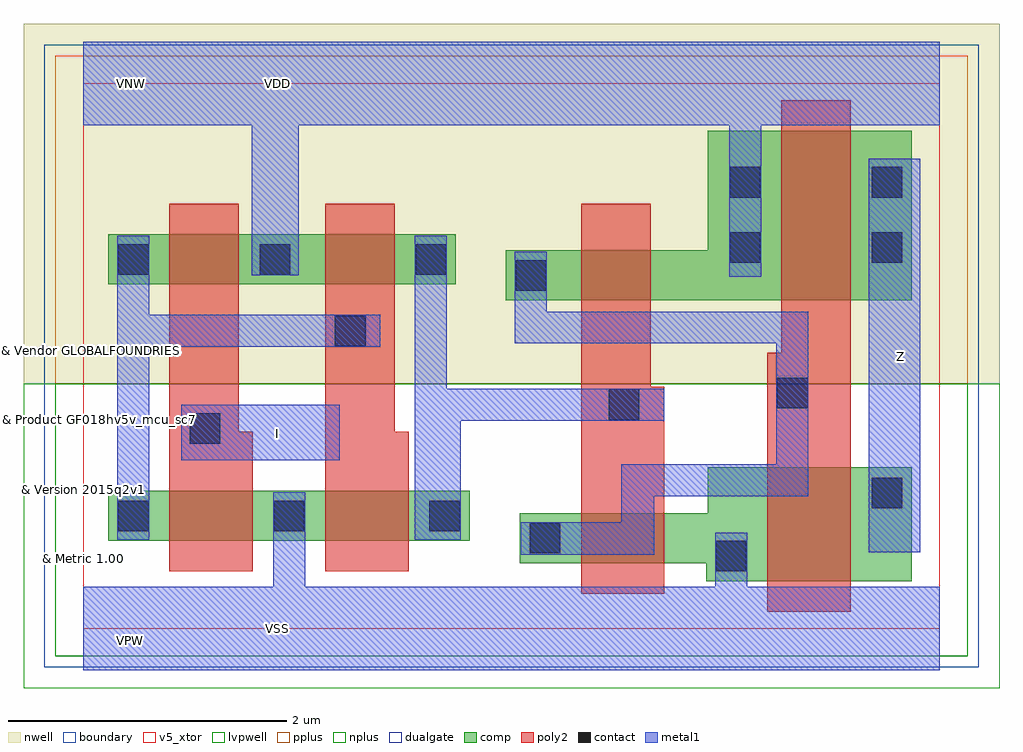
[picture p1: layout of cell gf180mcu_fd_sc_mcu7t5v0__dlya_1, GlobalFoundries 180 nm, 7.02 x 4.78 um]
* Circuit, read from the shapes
.subckt gf180mcu_fd_sc_mcu7t5v0__dlya_1 I VDD VNW VSS Z
XM1 VSS I n1 VSUBS nfet_05v0 w=0.36u l=0.6u
XM2 n2 n1 VSS VSUBS nfet_05v0 w=0.36u l=0.6u
XM3 VSS n2 n3 VSUBS nfet_05v0 w=0.36u l=0.6u
XM4 Z n3 VSS VSUBS nfet_05v0 w=0.82u l=0.6u
XM5 VDD I n1 VNW pfet_05v0 w=0.36u l=0.5u
XM6 n2 n1 VDD VNW pfet_05v0 w=0.36u l=0.5u
XM7 VDD n2 n3 VNW pfet_05v0 w=0.36u l=0.5u
XM8 Z n3 VDD VNW pfet_05v0 w=1.22u l=0.5u
.ends

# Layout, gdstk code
import gdstk
lib = gdstk.Library(unit=1e-6, precision=1e-09)
def R(c, l, rs):  # rectangles x0, y0, x1, y1
    for r in rs: c.add(gdstk.rectangle(r[:2], r[2:], *l))
def A(c, l, x, y, w, h, nx, ny, dx, dy):  # array of equal rectangles
    R(c, l, [(x+i*dx, y+j*dy, x+i*dx+w, y+j*dy+h) for i in range(nx) for j in range(ny)])
def P(c, l, *ps):  # polygons
    for p in ps: c.add(gdstk.Polygon(p, *l))
boundary = (0, 0)
nwell = (21, 0)
comp = (22, 0)
poly2 = (30, 0)
pplus = (31, 0)
nplus = (32, 0)
contact = (33, 0)
metal1 = (34, 0)
dualgate = (55, 0)
v5_xtor = (112, 1)
lvpwell = (204, 0)

gf180mcu_fd_sc_mcu7t5v0_ = lib.new_cell('gf180mcu_fd_sc_mcu7t5v0__dlya_1')
R(gf180mcu_fd_sc_mcu7t5v0_, boundary, [(0,0,6.16,3.92)])
R(gf180mcu_fd_sc_mcu7t5v0_, nwell, [(-0.43,1.76,6.59,4.35)])
R(gf180mcu_fd_sc_mcu7t5v0_, comp, [(0.18,0.63,2.78,0.99), (0.18,2.475,2.68,2.835)])
P(gf180mcu_fd_sc_mcu7t5v0_, comp, [(4.48,0.34),(4.48,0.47),(3.14,0.47),(3.14,0.83),(4.49,0.83),(4.49,1.16),(5.96,1.16),(5.96,0.34)],
  [(3.04,2.36),(3.04,2.72),(4.49,2.72),(4.49,3.58),(5.96,3.58),(5.96,2.36)])
P(gf180mcu_fd_sc_mcu7t5v0_, poly2, [(0.62,0.41),(0.62,3.055),(1.12,3.055),(1.12,1.415),(1.22,1.415),(1.22,0.41)],
  [(1.74,0.41),(1.74,3.055),(2.24,3.055),(2.24,1.415),(2.34,1.415),(2.34,0.41)],
  [(3.58,0.25),(3.58,3.055),(4.08,3.055),(4.08,1.74),(4.18,1.74),(4.18,0.25)],
  [(4.92,0.12),(4.92,1.985),(5.02,1.985),(5.02,3.8),(5.52,3.8),(5.52,0.12)])
R(gf180mcu_fd_sc_mcu7t5v0_, pplus, [(-0.2,1.76,6.36,4.12)])
R(gf180mcu_fd_sc_mcu7t5v0_, nplus, [(-0.2,-0.2,6.36,1.76)])
A(gf180mcu_fd_sc_mcu7t5v0_, contact, 0.25, 0.7, 0.22, 0.22, 3, 1, 1.12, 0)
R(gf180mcu_fd_sc_mcu7t5v0_, contact, [(4.55,0.41,4.77,0.63), (3.21,0.54,3.43,0.76), (5.67,0.865,5.89,1.085), (0.765,1.33,0.985,1.55), (3.78,1.5,4,1.72), (4.99,1.585,5.21,1.805), (1.81,2.03,2.03,2.25), (3.11,2.43,3.33,2.65), (0.25,2.545,0.47,2.765), (1.27,2.545,1.49,2.765), (2.39,2.545,2.61,2.765), (4.65,2.63,4.87,2.85), (5.67,2.63,5.89,2.85), (4.65,3.1,4.87,3.32), (5.67,3.1,5.89,3.32)])
R(gf180mcu_fd_sc_mcu7t5v0_, metal1, [(5.65,0.55,6.02,3.38), (0.705,1.21,1.845,1.61)])
P(gf180mcu_fd_sc_mcu7t5v0_, metal1, [(0.245,0.64),(0.245,2.825),(0.475,2.825),(0.475,2.255),(2.135,2.255),(2.135,2.025),(0.475,2.025),(0.475,0.64)],
  [(2.385,0.64),(2.385,2.825),(2.615,2.825),(2.615,1.725),(4.18,1.725),(4.18,1.495),(2.715,1.495),(2.715,0.64)],
  [(3.145,0.53),(3.145,0.765),(3.87,0.765),(3.87,1.18),(4.985,1.18),(4.985,2.05),(3.105,2.05),(3.105,2.71),(3.335,2.71),(3.335,2.28),(5.215,2.28),(5.215,0.95),(4.105,0.95),(4.105,0.53)],
  [(0,-0.3),(0,0.3),(1.365,0.3),(1.365,0.98),(1.595,0.98),(1.595,0.3),(4.545,0.3),(4.545,0.69),(4.775,0.69),(4.775,0.3),(6.16,0.3),(6.16,-0.3)],
  [(4.645,2.53),(4.645,3.62),(1.55,3.62),(1.55,2.54),(1.21,2.54),(1.21,3.62),(0,3.62),(0,4.22),(6.16,4.22),(6.16,3.62),(4.875,3.62),(4.875,2.53)])
R(gf180mcu_fd_sc_mcu7t5v0_, dualgate, [(-0.28,-0.28,6.44,4.2)])
R(gf180mcu_fd_sc_mcu7t5v0_, v5_xtor, [(0,0,6.16,3.92)])
R(gf180mcu_fd_sc_mcu7t5v0_, lvpwell, [(-0.43,-0.43,6.59,1.76)])
gf180mcu_fd_sc_mcu7t5v0_.add(gdstk.Label('VSS', (1.4,0), layer=34, texttype=10))
gf180mcu_fd_sc_mcu7t5v0_.add(gdstk.Label('Z', (5.88,1.96), layer=34, texttype=10))
gf180mcu_fd_sc_mcu7t5v0_.add(gdstk.Label('I', (1.4,1.4), layer=34, texttype=10))
gf180mcu_fd_sc_mcu7t5v0_.add(gdstk.Label('VDD', (1.4,3.92), layer=34, texttype=10))
gf180mcu_fd_sc_mcu7t5v0_.add(gdstk.Label('& Vendor GLOBALFOUNDRIES', (0,2), layer=63, texttype=63))
gf180mcu_fd_sc_mcu7t5v0_.add(gdstk.Label('& Product GF018hv5v_mcu_sc7', (0,1.5), layer=63, texttype=63))
gf180mcu_fd_sc_mcu7t5v0_.add(gdstk.Label('& Version 2015q2v1', (0,1), layer=63, texttype=63))
gf180mcu_fd_sc_mcu7t5v0_.add(gdstk.Label('& Metric 1.00', (0,0.5), layer=63, texttype=63))
gf180mcu_fd_sc_mcu7t5v0_.add(gdstk.Label('VNW', (0.345,3.92), layer=21, texttype=10))
gf180mcu_fd_sc_mcu7t5v0_.add(gdstk.Label('VPW', (0.34,-0.085), layer=204, texttype=10))

lib.write_gds('gf180mcu_fd_sc_mcu7t5v0__dlya_1.gds')
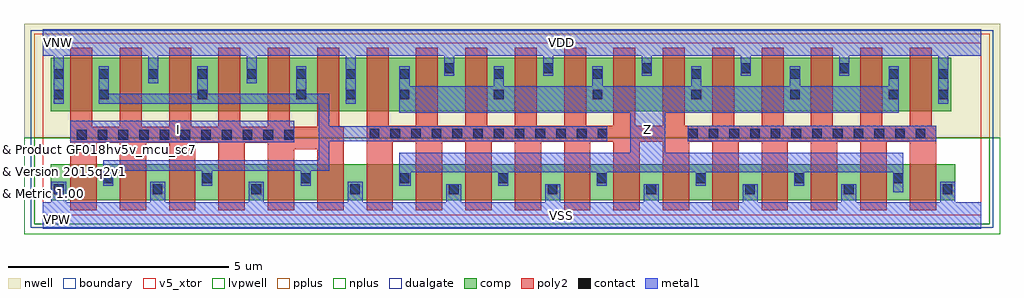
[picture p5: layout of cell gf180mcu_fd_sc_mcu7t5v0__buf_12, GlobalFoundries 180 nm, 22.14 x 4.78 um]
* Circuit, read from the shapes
.subckt gf180mcu_fd_sc_mcu7t5v0__buf_12 I VDD VNW VSS Z
XM1 n1 I VSS VSUBS nfet_05v0 w=0.82u l=0.6u m=6
XM2 Z n1 VSS VSUBS nfet_05v0 w=0.82u l=0.6u m=12
XM3 n1 I VDD VNW pfet_05v0 w=1.22u l=0.5u m=6
XM4 Z n1 VDD VNW pfet_05v0 w=1.22u l=0.5u m=12
.ends

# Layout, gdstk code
import gdstk
lib = gdstk.Library(unit=1e-6, precision=1e-09)
def R(c, l, rs):  # rectangles x0, y0, x1, y1
    for r in rs: c.add(gdstk.rectangle(r[:2], r[2:], *l))
def A(c, l, x, y, w, h, nx, ny, dx, dy):  # array of equal rectangles
    R(c, l, [(x+i*dx, y+j*dy, x+i*dx+w, y+j*dy+h) for i in range(nx) for j in range(ny)])
def P(c, l, *ps):  # polygons
    for p in ps: c.add(gdstk.Polygon(p, *l))
boundary = (0, 0)
nwell = (21, 0)
comp = (22, 0)
poly2 = (30, 0)
pplus = (31, 0)
nplus = (32, 0)
contact = (33, 0)
metal1 = (34, 0)
dualgate = (55, 0)
v5_xtor = (112, 1)
lvpwell = (204, 0)

gf180mcu_fd_sc_mcu7t5v0_ = lib.new_cell('gf180mcu_fd_sc_mcu7t5v0__buf_12')
R(gf180mcu_fd_sc_mcu7t5v0_, boundary, [(0,0,21.28,3.92)])
R(gf180mcu_fd_sc_mcu7t5v0_, nwell, [(-0.43,1.76,21.71,4.35)])
R(gf180mcu_fd_sc_mcu7t5v0_, comp, [(0.18,0.34,20.7,1.16), (0.18,2.36,20.6,3.58)])
P(gf180mcu_fd_sc_mcu7t5v0_, poly2, [(0.62,0.12),(0.62,3.8),(1.12,3.8),(1.12,2.01),(1.74,2.01),(1.74,3.8),(2.24,3.8),(2.24,2.01),(2.86,2.01),(2.86,3.8),(3.36,3.8),(3.36,2.01),(3.98,2.01),(3.98,3.8),(4.48,3.8),(4.48,2.01),(5.1,2.01),(5.1,3.8),(5.6,3.8),(5.6,2.01),(6.22,2.01),(6.22,3.8),(6.72,3.8),(6.72,2.01),(6.82,2.01),(6.82,0.12),(6.22,0.12),(6.22,1.5),(5.7,1.5),(5.7,0.12),(5.1,0.12),(5.1,1.65),(4.58,1.65),(4.58,0.12),(3.98,0.12),(3.98,1.65),(3.46,1.65),(3.46,0.12),(2.86,0.12),(2.86,1.65),(2.34,1.65),(2.34,0.12),(1.74,0.12),(1.74,1.65),(1.22,1.65),(1.22,0.12)],
  [(7.34,0.12),(7.34,3.8),(7.84,3.8),(7.84,2.035),(8.46,2.035),(8.46,3.8),(8.96,3.8),(8.96,2.035),(9.58,2.035),(9.58,3.8),(10.08,3.8),(10.08,2.035),(10.7,2.035),(10.7,3.8),(11.2,3.8),(11.2,2.035),(11.82,2.035),(11.82,3.8),(12.32,3.8),(12.32,2.035),(12.94,2.035),(12.94,3.8),(13.44,3.8),(13.44,2.035),(14.06,2.035),(14.06,3.8),(14.56,3.8),(14.56,2.035),(15.18,2.035),(15.18,3.8),(15.68,3.8),(15.68,2.035),(16.3,2.035),(16.3,3.8),(16.8,3.8),(16.8,2.035),(17.42,2.035),(17.42,3.8),(17.92,3.8),(17.92,2.035),(18.54,2.035),(18.54,3.8),(19.04,3.8),(19.04,2.035),(19.66,2.035),(19.66,3.8),(20.16,3.8),(20.16,2.035),(20.26,2.035),(20.26,0.12),(19.66,0.12),(19.66,1.675),(19.14,1.675),(19.14,0.12),(18.54,0.12),(18.54,1.675),(18.02,1.675),(18.02,0.12),(17.42,0.12),(17.42,1.675),(16.9,1.675),(16.9,0.12),(16.3,0.12),(16.3,1.675),(15.78,1.675),(15.78,0.12),(15.18,0.12),(15.18,1.675),(14.66,1.675),(14.66,0.12),(14.06,0.12),(14.06,1.675),(13.54,1.675),(13.54,0.12),(12.94,0.12),(12.94,1.675),(12.42,1.675),(12.42,0.12),(11.82,0.12),(11.82,1.675),(11.3,1.675),(11.3,0.12),(10.7,0.12),(10.7,1.675),(10.18,1.675),(10.18,0.12),(9.58,0.12),(9.58,1.675),(9.06,1.675),(9.06,0.12),(8.46,0.12),(8.46,1.675),(7.94,1.675),(7.94,0.12)])
R(gf180mcu_fd_sc_mcu7t5v0_, pplus, [(-0.2,1.76,21.48,4.12)])
R(gf180mcu_fd_sc_mcu7t5v0_, nplus, [(-0.2,-0.2,21.48,1.76)])
A(gf180mcu_fd_sc_mcu7t5v0_, contact, 0.25, 0.485, 0.22, 0.22, 10, 1, 2.24, 0)
A(gf180mcu_fd_sc_mcu7t5v0_, contact, 1.37, 0.735, 0.22, 0.22, 9, 1, 2.24, 0)
A(gf180mcu_fd_sc_mcu7t5v0_, contact, 0.77, 1.72, 0.22, 0.22, 11, 1, 0.47, 0)
A(gf180mcu_fd_sc_mcu7t5v0_, contact, 7.41, 1.745, 0.22, 0.22, 12, 1, 0.47, 0)
A(gf180mcu_fd_sc_mcu7t5v0_, contact, 14.63, 1.745, 0.22, 0.22, 12, 1, 0.47, 0)
A(gf180mcu_fd_sc_mcu7t5v0_, contact, 1.27, 2.63, 0.22, 0.22, 3, 1, 2.24, 0)
A(gf180mcu_fd_sc_mcu7t5v0_, contact, 10.23, 2.63, 0.22, 0.22, 5, 2, 2.24, 0.47)
A(gf180mcu_fd_sc_mcu7t5v0_, contact, 1.27, 3.1, 0.22, 0.22, 6, 1, 1.12, 0)
A(gf180mcu_fd_sc_mcu7t5v0_, contact, 9.11, 3.23, 0.22, 0.22, 5, 1, 2.24, 0)
R(gf180mcu_fd_sc_mcu7t5v0_, contact, [(0.25,2.63,0.47,2.85), (6.87,2.63,7.09,2.85), (8.09,2.63,8.31,2.85), (20.31,2.63,20.53,2.85), (0.25,3.1,0.47,3.32), (8.09,3.1,8.31,3.32), (20.31,3.1,20.53,3.32)])
R(gf180mcu_fd_sc_mcu7t5v0_, metal1, [(0.62,1.66,5.7,2.15), (14.625,1.685,20.26,2.03)])
P(gf180mcu_fd_sc_mcu7t5v0_, metal1, [(1.365,0.675),(1.365,1.25),(6.26,1.25),(6.26,2.53),(1.265,2.53),(1.265,3.38),(1.495,3.38),(1.495,2.76),(3.505,2.76),(3.505,3.38),(3.735,3.38),(3.735,2.76),(5.745,2.76),(5.745,3.38),(5.975,3.38),(5.975,2.76),(6.495,2.76),(6.495,2.025),(12.805,2.025),(12.805,1.685),(6.495,1.685),(6.495,1.015),(6.075,1.015),(6.075,0.675),(5.845,0.675),(5.845,1.015),(3.835,1.015),(3.835,0.675),(3.605,0.675),(3.605,1.015),(1.595,1.015),(1.595,0.675)],
  [(19.285,0.53),(19.285,0.98),(17.275,0.98),(17.275,0.675),(17.045,0.675),(17.045,0.98),(15.035,0.98),(15.035,0.675),(14.805,0.675),(14.805,0.98),(12.795,0.98),(12.795,0.675),(12.565,0.675),(12.565,0.98),(10.555,0.98),(10.555,0.675),(10.325,0.675),(10.325,0.98),(8.345,0.98),(8.345,0.675),(8.085,0.675),(8.085,1.42),(13.32,1.42),(13.32,2.33),(8.085,2.33),(8.085,3.38),(8.315,3.38),(8.315,2.93),(10.225,2.93),(10.225,3.38),(10.455,3.38),(10.455,2.93),(12.465,2.93),(12.465,3.38),(12.695,3.38),(12.695,2.93),(14.705,2.93),(14.705,3.38),(14.935,3.38),(14.935,2.93),(16.945,2.93),(16.945,3.38),(17.175,3.38),(17.175,2.93),(19.185,2.93),(19.185,3.38),(19.415,3.38),(19.415,2.33),(14.12,2.33),(14.12,1.42),(19.515,1.42),(19.515,0.53)],
  [(0,-0.3),(0,0.3),(0.19,0.3),(0.19,0.765),(0.53,0.765),(0.53,0.3),(2.43,0.3),(2.43,0.765),(2.77,0.765),(2.77,0.3),(4.67,0.3),(4.67,0.765),(5.01,0.765),(5.01,0.3),(6.91,0.3),(6.91,0.765),(7.25,0.765),(7.25,0.3),(9.15,0.3),(9.15,0.71),(9.49,0.71),(9.49,0.3),(11.39,0.3),(11.39,0.71),(11.73,0.71),(11.73,0.3),(13.63,0.3),(13.63,0.71),(13.97,0.71),(13.97,0.3),(15.87,0.3),(15.87,0.71),(16.21,0.71),(16.21,0.3),(18.11,0.3),(18.11,0.71),(18.45,0.71),(18.45,0.3),(20.35,0.3),(20.35,0.765),(20.69,0.765),(20.69,0.3),(21.28,0.3),(21.28,-0.3)],
  [(0.245,2.53),(0.245,3.62),(0,3.62),(0,4.22),(21.28,4.22),(21.28,3.62),(20.535,3.62),(20.535,2.53),(20.305,2.53),(20.305,3.62),(18.295,3.62),(18.295,3.17),(18.065,3.17),(18.065,3.62),(16.055,3.62),(16.055,3.17),(15.825,3.17),(15.825,3.62),(13.815,3.62),(13.815,3.17),(13.585,3.17),(13.585,3.62),(11.575,3.62),(11.575,3.17),(11.345,3.17),(11.345,3.62),(9.335,3.62),(9.335,3.17),(9.105,3.17),(9.105,3.62),(7.095,3.62),(7.095,2.53),(6.865,2.53),(6.865,3.62),(4.855,3.62),(4.855,3),(4.625,3),(4.625,3.62),(2.615,3.62),(2.615,3),(2.385,3),(2.385,3.62),(0.475,3.62),(0.475,2.53)])
R(gf180mcu_fd_sc_mcu7t5v0_, dualgate, [(-0.28,-0.28,21.56,4.2)])
R(gf180mcu_fd_sc_mcu7t5v0_, v5_xtor, [(0,0,21.28,3.92)])
R(gf180mcu_fd_sc_mcu7t5v0_, lvpwell, [(-0.43,-0.43,21.71,1.76)])
gf180mcu_fd_sc_mcu7t5v0_.add(gdstk.Label('Z', (13.72,1.96), layer=34, texttype=10))
gf180mcu_fd_sc_mcu7t5v0_.add(gdstk.Label('I', (3.08,1.96), layer=34, texttype=10))
gf180mcu_fd_sc_mcu7t5v0_.add(gdstk.Label('VDD', (11.76,3.92), layer=34, texttype=10))
gf180mcu_fd_sc_mcu7t5v0_.add(gdstk.Label('VSS', (11.76,0), layer=34, texttype=10))
gf180mcu_fd_sc_mcu7t5v0_.add(gdstk.Label('& Vendor GLOBALFOUNDRIES', (0,2), layer=63, texttype=63))
gf180mcu_fd_sc_mcu7t5v0_.add(gdstk.Label('& Product GF018hv5v_mcu_sc7', (0,1.5), layer=63, texttype=63))
gf180mcu_fd_sc_mcu7t5v0_.add(gdstk.Label('& Version 2015q2v1', (0,1), layer=63, texttype=63))
gf180mcu_fd_sc_mcu7t5v0_.add(gdstk.Label('& Metric 1.00', (0,0.5), layer=63, texttype=63))
gf180mcu_fd_sc_mcu7t5v0_.add(gdstk.Label('VNW', (0.345,3.92), layer=21, texttype=10))
gf180mcu_fd_sc_mcu7t5v0_.add(gdstk.Label('VPW', (0.34,-0.085), layer=204, texttype=10))

lib.write_gds('gf180mcu_fd_sc_mcu7t5v0__buf_12.gds')
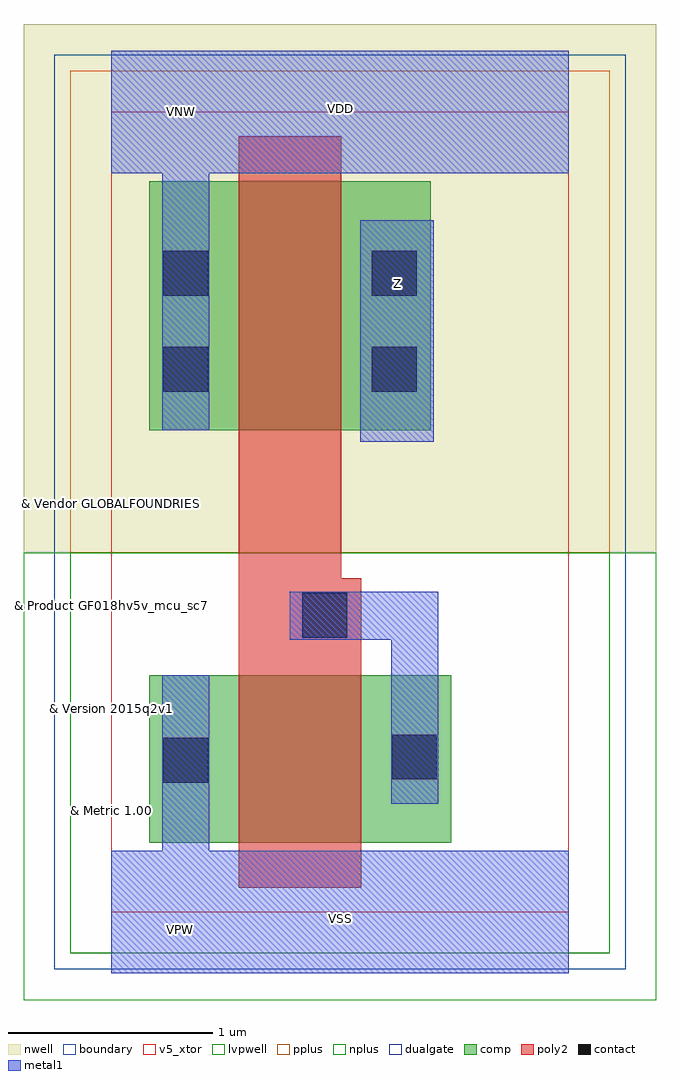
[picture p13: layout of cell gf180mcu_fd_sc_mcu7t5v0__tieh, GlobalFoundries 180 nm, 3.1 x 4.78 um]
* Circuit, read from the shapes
.subckt gf180mcu_fd_sc_mcu7t5v0__tieh VDD VNW VSS Z
XM1 n1 n1 VSS VSUBS nfet_05v0 w=0.82u l=0.6u
XM2 Z n1 VDD VNW pfet_05v0 w=1.22u l=0.5u
.ends

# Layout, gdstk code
import gdstk
lib = gdstk.Library(unit=1e-6, precision=1e-09)
def R(c, l, rs):  # rectangles x0, y0, x1, y1
    for r in rs: c.add(gdstk.rectangle(r[:2], r[2:], *l))
def P(c, l, *ps):  # polygons
    for p in ps: c.add(gdstk.Polygon(p, *l))
boundary = (0, 0)
nwell = (21, 0)
comp = (22, 0)
poly2 = (30, 0)
pplus = (31, 0)
nplus = (32, 0)
contact = (33, 0)
metal1 = (34, 0)
dualgate = (55, 0)
v5_xtor = (112, 1)
lvpwell = (204, 0)

gf180mcu_fd_sc_mcu7t5v0_ = lib.new_cell('gf180mcu_fd_sc_mcu7t5v0__tieh')
R(gf180mcu_fd_sc_mcu7t5v0_, boundary, [(0,0,2.24,3.92)])
R(gf180mcu_fd_sc_mcu7t5v0_, nwell, [(-0.43,1.76,2.67,4.35)])
R(gf180mcu_fd_sc_mcu7t5v0_, comp, [(0.185,0.34,1.665,1.16), (0.185,2.36,1.565,3.58)])
P(gf180mcu_fd_sc_mcu7t5v0_, poly2, [(0.625,0.12),(0.625,3.8),(1.125,3.8),(1.125,1.635),(1.225,1.635),(1.225,0.12)])
R(gf180mcu_fd_sc_mcu7t5v0_, pplus, [(-0.2,1.76,2.44,4.12)])
R(gf180mcu_fd_sc_mcu7t5v0_, nplus, [(-0.2,-0.2,2.44,1.76)])
R(gf180mcu_fd_sc_mcu7t5v0_, contact, [(0.255,0.635,0.475,0.855), (1.375,0.65,1.595,0.87), (0.935,1.345,1.155,1.565), (0.255,2.55,0.475,2.77), (1.275,2.55,1.495,2.77), (0.255,3.02,0.475,3.24), (1.275,3.02,1.495,3.24)])
R(gf180mcu_fd_sc_mcu7t5v0_, metal1, [(1.22,2.305,1.58,3.39)])
P(gf180mcu_fd_sc_mcu7t5v0_, metal1, [(1.37,0.53),(1.37,1.335),(0.875,1.335),(0.875,1.57),(1.6,1.57),(1.6,0.53)],
  [(0,-0.3),(0,0.3),(0.25,0.3),(0.25,1.16),(0.48,1.16),(0.48,0.3),(2.24,0.3),(2.24,-0.3)],
  [(0.25,2.36),(0.25,3.62),(0,3.62),(0,4.22),(2.24,4.22),(2.24,3.62),(0.48,3.62),(0.48,2.36)])
R(gf180mcu_fd_sc_mcu7t5v0_, dualgate, [(-0.28,-0.28,2.52,4.2)])
R(gf180mcu_fd_sc_mcu7t5v0_, v5_xtor, [(0,0,2.24,3.92)])
R(gf180mcu_fd_sc_mcu7t5v0_, lvpwell, [(-0.43,-0.43,2.67,1.76)])
gf180mcu_fd_sc_mcu7t5v0_.add(gdstk.Label('Z', (1.4,3.08), layer=34, texttype=10))
gf180mcu_fd_sc_mcu7t5v0_.add(gdstk.Label('VDD', (1.12,3.935), layer=34, texttype=10))
gf180mcu_fd_sc_mcu7t5v0_.add(gdstk.Label('VSS', (1.12,-0.03), layer=34, texttype=10))
gf180mcu_fd_sc_mcu7t5v0_.add(gdstk.Label('& Vendor GLOBALFOUNDRIES', (0,2), layer=63, texttype=63))
gf180mcu_fd_sc_mcu7t5v0_.add(gdstk.Label('& Product GF018hv5v_mcu_sc7', (0,1.5), layer=63, texttype=63))
gf180mcu_fd_sc_mcu7t5v0_.add(gdstk.Label('& Version 2015q2v1', (0,1), layer=63, texttype=63))
gf180mcu_fd_sc_mcu7t5v0_.add(gdstk.Label('& Metric 1.00', (0,0.5), layer=63, texttype=63))
gf180mcu_fd_sc_mcu7t5v0_.add(gdstk.Label('VNW', (0.345,3.92), layer=21, texttype=10))
gf180mcu_fd_sc_mcu7t5v0_.add(gdstk.Label('VPW', (0.34,-0.085), layer=204, texttype=10))

lib.write_gds('gf180mcu_fd_sc_mcu7t5v0__tieh.gds')
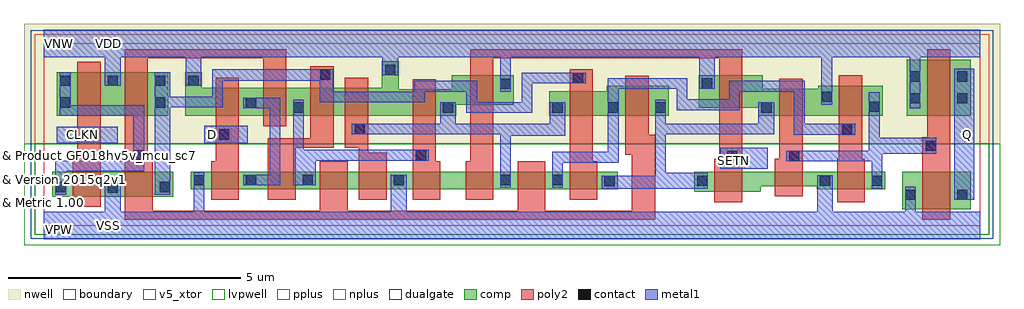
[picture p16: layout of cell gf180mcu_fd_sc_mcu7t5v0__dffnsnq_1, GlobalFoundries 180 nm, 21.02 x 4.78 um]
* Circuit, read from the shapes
.subckt gf180mcu_fd_sc_mcu7t5v0__dffnsnq_1 CLKN D Q SETN VDD VNW VSS
XM1 VSS CLKN n1 VSUBS nfet_05v0 w=0.54u l=0.6u
XM2 n2 n1 VSS VSUBS nfet_05v0 w=0.54u l=0.6u
XM3 n3 D VSS VSUBS nfet_05v0 w=0.38u l=0.6u
XM4 n4 n2 n3 VSUBS nfet_05v0 w=0.38u l=0.6u
XM5 n5 n1 n4 VSUBS nfet_05v0 w=0.38u l=0.6u
XM6 VSS n6 n5 VSUBS nfet_05v0 w=0.38u l=0.6u
XM7 n7 n4 VSS VSUBS nfet_05v0 w=0.38u l=0.6u
XM8 n6 SETN n7 VSUBS nfet_05v0 w=0.38u l=0.6u
XM9 n8 n1 n6 VSUBS nfet_05v0 w=0.38u l=0.6u
XM10 n9 n2 n8 VSUBS nfet_05v0 w=0.38u l=0.6u
XM11 n10 SETN n9 VSUBS nfet_05v0 w=0.435u l=0.6u
XM12 VSS n11 n10 VSUBS nfet_05v0 w=0.31u l=0.6u
XM13 n11 n8 VSS VSUBS nfet_05v0 w=0.375u l=0.6u
XM14 Q n11 VSS VSUBS nfet_05v0 w=0.815u l=0.6u
XM15 VDD CLKN n1 VNW pfet_05v0 w=0.94u l=0.5u
XM16 n2 n1 VDD VNW pfet_05v0 w=0.94u l=0.5u
XM17 n3 D VDD VNW pfet_05v0 w=0.605u l=0.5u
XM18 n4 n1 n3 VNW pfet_05v0 w=0.605u l=0.5u
XM19 n12 n2 n4 VNW pfet_05v0 w=0.605u l=0.5u
XM20 VDD n6 n12 VNW pfet_05v0 w=0.605u l=0.5u
XM21 n6 n4 VDD VNW pfet_05v0 w=0.57u l=0.5u
XM22 VDD SETN n6 VNW pfet_05v0 w=0.63u l=0.5u
XM23 n8 n2 n6 VNW pfet_05v0 w=0.535u l=0.5u
XM24 n9 n1 n8 VNW pfet_05v0 w=0.65u l=0.5u
XM25 n9 SETN VDD VNW pfet_05v0 w=0.705u l=0.5u
XM26 VDD n11 n9 VNW pfet_05v0 w=0.58u l=0.5u
XM27 n11 n8 VDD VNW pfet_05v0 w=0.655u l=0.5u
XM28 Q n11 VDD VNW pfet_05v0 w=1.215u l=0.5u
.ends

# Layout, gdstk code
import gdstk
lib = gdstk.Library(unit=1e-6, precision=1e-09)
def R(c, l, rs):  # rectangles x0, y0, x1, y1
    for r in rs: c.add(gdstk.rectangle(r[:2], r[2:], *l))
def A(c, l, x, y, w, h, nx, ny, dx, dy):  # array of equal rectangles
    R(c, l, [(x+i*dx, y+j*dy, x+i*dx+w, y+j*dy+h) for i in range(nx) for j in range(ny)])
def P(c, l, *ps):  # polygons
    for p in ps: c.add(gdstk.Polygon(p, *l))
boundary = (0, 0)
nwell = (21, 0)
comp = (22, 0)
poly2 = (30, 0)
pplus = (31, 0)
nplus = (32, 0)
contact = (33, 0)
metal1 = (34, 0)
dualgate = (55, 0)
v5_xtor = (112, 1)
lvpwell = (204, 0)

gf180mcu_fd_sc_mcu7t5v0_ = lib.new_cell('gf180mcu_fd_sc_mcu7t5v0__dffnsnq_1')
R(gf180mcu_fd_sc_mcu7t5v0_, boundary, [(0,0,20.16,3.92)])
R(gf180mcu_fd_sc_mcu7t5v0_, nwell, [(-0.43,1.76,20.59,4.35)])
R(gf180mcu_fd_sc_mcu7t5v0_, comp, [(18.48,0.345,19.96,1.16), (0.18,0.62,2.78,1.16), (3.16,0.78,12.36,1.16), (0.28,2.36,2.68,3.3), (18.58,2.36,19.96,3.575)])
P(gf180mcu_fd_sc_mcu7t5v0_, comp, [(3.04,2.36),(3.04,3.3),(3.4,3.3),(3.4,2.965),(7.28,2.965),(7.28,3.535),(7.64,3.535),(7.64,2.93),(8.78,2.93),(8.78,3.235),(10.12,3.235),(10.12,2.605),(8.88,2.605),(8.88,2.36)],
  [(10.88,2.36),(10.88,2.895),(12.12,2.895),(12.12,3.01),(13.46,3.01),(13.46,2.36)],
  [(15.38,2.36),(15.38,2.535),(14.1,2.535),(14.1,3.24),(15.48,3.24),(15.48,2.94),(16.68,2.94),(16.68,3.015),(18.06,3.015),(18.06,2.36)],
  [(14,0.725),(14,1.16),(18.12,1.16),(18.12,0.785),(16.64,0.785),(16.64,0.85),(15.44,0.85),(15.44,0.725)])
P(gf180mcu_fd_sc_mcu7t5v0_, poly2, [(0.62,0.4),(0.62,1.44),(0.72,1.44),(0.72,3.525),(1.22,3.525),(1.22,0.4)],
  [(3.6,0.56),(3.6,1.38),(3.7,1.38),(3.7,3.185),(4.2,3.185),(4.2,0.56)],
  [(4.82,0.56),(4.82,1.88),(5.74,1.88),(5.74,3.425),(6.24,3.425),(6.24,1.68),(5.42,1.68),(5.42,0.56)],
  [(6.78,0.56),(6.78,1.68),(6.48,1.68),(6.48,3.185),(6.98,3.185),(6.98,1.57),(7.38,1.57),(7.38,0.56)],
  [(7.94,0.56),(7.94,3.15),(8.44,3.15),(8.44,1.38),(8.54,1.38),(8.54,0.56)],
  [(11.32,0.56),(11.32,3.36),(11.82,3.36),(11.82,1.38),(11.92,1.38),(11.92,0.56)],
  [(1.74,0.12),(1.74,3.8),(5.22,3.8),(5.22,2.14),(4.72,2.14),(4.72,3.6),(2.24,3.6),(2.24,1.44),(2.34,1.44),(2.34,0.32),(5.94,0.32),(5.94,1.38),(6.54,1.38),(6.54,0.32),(10.2,0.32),(10.2,1.38),(10.8,1.38),(10.8,0.32),(12.66,0.32),(12.66,1.52),(12.52,1.52),(12.52,3.23),(13.02,3.23),(13.02,1.96),(13.16,1.96),(13.16,0.12)],
  [(14.44,0.505),(14.44,1.44),(14.54,1.44),(14.54,3.6),(9.68,3.6),(9.68,0.56),(9.08,0.56),(9.08,1.38),(9.18,1.38),(9.18,3.8),(15.04,3.8),(15.04,0.505)],
  [(15.74,0.63),(15.74,1.44),(15.84,1.44),(15.84,3.16),(16.34,3.16),(16.34,0.63)],
  [(17.08,0.505),(17.08,1.44),(17.12,1.44),(17.12,3.24),(17.62,3.24),(17.62,1.44),(17.68,1.44),(17.68,0.505)],
  [(18.92,0.12),(18.92,1.9),(19.02,1.9),(19.02,3.8),(19.52,3.8),(19.52,0.12)])
R(gf180mcu_fd_sc_mcu7t5v0_, pplus, [(-0.2,1.76,20.36,4.12)])
R(gf180mcu_fd_sc_mcu7t5v0_, nplus, [(-0.2,-0.2,20.36,1.76)])
A(gf180mcu_fd_sc_mcu7t5v0_, contact, 0.35, 3.01, 0.22, 0.22, 3, 1, 1.02, 0)
R(gf180mcu_fd_sc_mcu7t5v0_, contact, [(18.55,0.555,18.77,0.775), (19.67,0.555,19.89,0.775), (1.37,0.71,1.59,0.93), (0.25,0.72,0.47,0.94), (2.49,0.72,2.71,0.94), (12.07,0.85,12.29,1.07), (14.07,0.855,14.29,1.075), (16.71,0.855,16.93,1.075), (17.83,0.855,18.05,1.075), (3.23,0.865,3.45,1.085), (7.53,0.865,7.75,1.085), (4.35,0.87,4.57,1.09), (5.57,0.87,5.79,1.09), (9.83,0.87,10.05,1.09), (10.95,0.87,11.17,1.09), (14.715,1.39,14.935,1.61), (16.05,1.39,16.27,1.61), (1.93,1.405,2.15,1.625), (8.01,1.405,8.23,1.625), (18.99,1.61,19.21,1.83), (0.79,1.825,1.01,2.045), (3.77,1.85,3.99,2.07), (6.69,1.97,6.91,2.19), (17.19,1.97,17.41,2.19), (5.37,2.43,5.59,2.65), (8.59,2.43,8.81,2.65), (10.95,2.43,11.17,2.65), (12.15,2.43,12.37,2.65), (13.17,2.43,13.39,2.65), (15.45,2.43,15.67,2.65), (17.77,2.45,17.99,2.67), (4.35,2.525,4.57,2.745), (0.35,2.54,0.57,2.76), (2.39,2.54,2.61,2.76), (18.65,2.63,18.87,2.85), (19.67,2.63,19.89,2.85), (16.75,2.66,16.97,2.88), (9.83,2.945,10.05,3.165), (14.17,2.95,14.39,3.17), (3.11,3.01,3.33,3.23), (11.39,3.07,11.61,3.29), (18.65,3.1,18.87,3.32), (19.67,3.1,19.89,3.32), (5.95,3.135,6.17,3.355), (7.35,3.245,7.57,3.465)])
R(gf180mcu_fd_sc_mcu7t5v0_, metal1, [(19.61,0.55,20.04,3.38), (14.56,1.22,15.59,1.67), (0.28,1.77,1.59,2.13), (3.45,1.77,4.39,2.15)])
P(gf180mcu_fd_sc_mcu7t5v0_, metal1, [(0.245,0.66),(0.245,1.395),(1.925,1.395),(1.925,2.36),(0.345,2.36),(0.345,3.3),(0.575,3.3),(0.575,2.595),(2.155,2.595),(2.155,1.165),(0.475,1.165),(0.475,0.66)],
  [(4.29,0.865),(4.29,1.095),(4.86,1.095),(4.86,2.52),(4.29,2.52),(4.29,2.75),(5.09,2.75),(5.09,0.865)],
  [(5.365,0.865),(5.365,2.71),(5.595,2.71),(5.595,1.63),(8.29,1.63),(8.29,1.395),(5.85,1.395),(5.85,0.865)],
  [(9.825,0.81),(9.825,1.965),(6.63,1.965),(6.63,2.195),(8.53,2.195),(8.53,2.655),(8.87,2.655),(8.87,2.195),(10.89,2.195),(10.89,2.655),(11.23,2.655),(11.23,1.93),(10.055,1.93),(10.055,0.81)],
  [(2.385,0.66),(2.385,3.3),(2.715,3.3),(2.715,2.775),(3.62,2.775),(3.62,3.36),(6.23,3.36),(6.23,2.88),(7.975,2.88),(7.975,3.115),(9.33,3.115),(9.33,2.655),(10.285,2.655),(10.285,3.295),(11.67,3.295),(11.67,3.065),(10.515,3.065),(10.515,2.425),(9.1,2.425),(9.1,2.885),(8.205,2.885),(8.205,2.65),(5.94,2.65),(5.94,3.12),(3.85,3.12),(3.85,2.545),(2.715,2.545),(2.715,0.66)],
  [(12.01,0.795),(12.01,1.075),(13.165,1.075),(13.165,2.71),(13.395,2.71),(13.395,2.195),(15.38,2.195),(15.38,2.655),(15.73,2.655),(15.73,1.965),(13.395,1.965),(13.395,1.135),(14.295,1.135),(14.295,0.795)],
  [(10.945,0.81),(10.945,1.585),(12.145,1.585),(12.145,3.175),(13.855,3.175),(13.855,2.715),(14.755,2.715),(14.755,3.12),(16.38,3.12),(16.38,2.195),(17.47,2.195),(17.47,1.96),(16.15,1.96),(16.15,2.885),(14.985,2.885),(14.985,2.48),(13.625,2.48),(13.625,2.94),(12.375,2.94),(12.375,1.355),(11.175,1.355),(11.175,0.81)],
  [(17.825,0.795),(17.825,1.385),(15.99,1.385),(15.99,1.615),(17.765,1.615),(17.765,2.875),(17.995,2.875),(17.995,1.895),(19.215,1.895),(19.215,1.545),(18.055,1.545),(18.055,0.795)],
  [(0,-0.3),(0,0.3),(1.31,0.3),(1.31,0.935),(1.65,0.935),(1.65,0.3),(3.225,0.3),(3.225,1.145),(3.455,1.145),(3.455,0.3),(7.47,0.3),(7.47,1.09),(7.81,1.09),(7.81,0.3),(16.65,0.3),(16.65,1.08),(16.99,1.08),(16.99,0.3),(18.545,0.3),(18.545,0.835),(18.775,0.835),(18.775,0.3),(20.16,0.3),(20.16,-0.3)],
  [(18.645,2.53),(18.645,3.62),(16.975,3.62),(16.975,2.6),(16.745,2.6),(16.745,3.62),(14.45,3.62),(14.45,2.945),(14.11,2.945),(14.11,3.62),(10.055,3.62),(10.055,2.885),(9.825,2.885),(9.825,3.62),(7.63,3.62),(7.63,3.24),(7.29,3.24),(7.29,3.62),(3.39,3.62),(3.39,3.005),(3.05,3.005),(3.05,3.62),(1.65,3.62),(1.65,3.005),(1.31,3.005),(1.31,3.62),(0,3.62),(0,4.22),(20.16,4.22),(20.16,3.62),(18.875,3.62),(18.875,2.53)])
R(gf180mcu_fd_sc_mcu7t5v0_, dualgate, [(-0.28,-0.28,20.44,4.2)])
R(gf180mcu_fd_sc_mcu7t5v0_, v5_xtor, [(0,0,20.16,3.92)])
R(gf180mcu_fd_sc_mcu7t5v0_, lvpwell, [(-0.43,-0.43,20.59,1.76)])
gf180mcu_fd_sc_mcu7t5v0_.add(gdstk.Label('CLKN', (0.84,1.96), layer=34, texttype=10))
gf180mcu_fd_sc_mcu7t5v0_.add(gdstk.Label('Q', (19.88,1.96), layer=34, texttype=10))
gf180mcu_fd_sc_mcu7t5v0_.add(gdstk.Label('SETN', (14.84,1.4), layer=34, texttype=10))
gf180mcu_fd_sc_mcu7t5v0_.add(gdstk.Label('VDD', (1.4,3.92), layer=34, texttype=10))
gf180mcu_fd_sc_mcu7t5v0_.add(gdstk.Label('VSS', (1.4,0), layer=34, texttype=10))
gf180mcu_fd_sc_mcu7t5v0_.add(gdstk.Label('D', (3.64,1.96), layer=34, texttype=10))
gf180mcu_fd_sc_mcu7t5v0_.add(gdstk.Label('& Vendor GLOBALFOUNDRIES', (0,2), layer=63, texttype=63))
gf180mcu_fd_sc_mcu7t5v0_.add(gdstk.Label('& Product GF018hv5v_mcu_sc7', (0,1.5), layer=63, texttype=63))
gf180mcu_fd_sc_mcu7t5v0_.add(gdstk.Label('& Version 2015q2v1', (0,1), layer=63, texttype=63))
gf180mcu_fd_sc_mcu7t5v0_.add(gdstk.Label('& Metric 1.00', (0,0.5), layer=63, texttype=63))
gf180mcu_fd_sc_mcu7t5v0_.add(gdstk.Label('VNW', (0.345,3.92), layer=21, texttype=10))
gf180mcu_fd_sc_mcu7t5v0_.add(gdstk.Label('VPW', (0.34,-0.085), layer=204, texttype=10))

lib.write_gds('gf180mcu_fd_sc_mcu7t5v0__dffnsnq_1.gds')
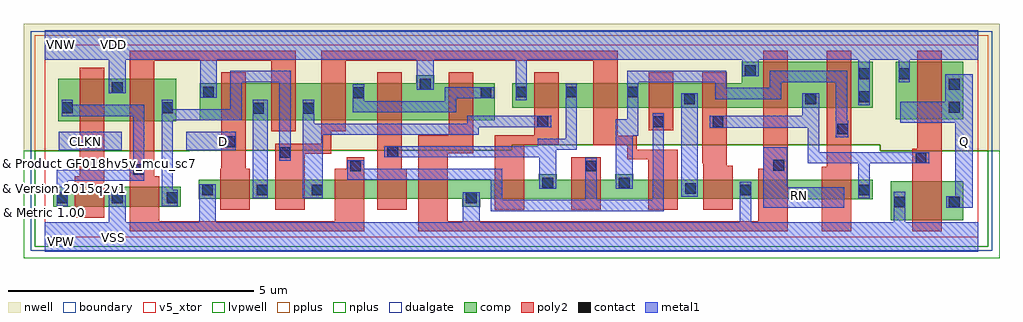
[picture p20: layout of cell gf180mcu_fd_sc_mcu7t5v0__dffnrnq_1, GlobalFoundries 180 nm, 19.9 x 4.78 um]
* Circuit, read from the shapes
.subckt gf180mcu_fd_sc_mcu7t5v0__dffnrnq_1 CLKN D Q RN VDD VNW VSS
XM1 VSS CLKN n1 VSUBS nfet_05v0 w=0.405u l=0.6u
XM2 n2 n1 VSS VSUBS nfet_05v0 w=0.405u l=0.6u
XM3 n3 D VSS VSUBS nfet_05v0 w=0.39u l=0.6u
XM4 n4 n2 n3 VSUBS nfet_05v0 w=0.39u l=0.6u
XM5 n5 n1 n4 VSUBS nfet_05v0 w=0.39u l=0.6u
XM6 n6 n7 n5 VSUBS nfet_05v0 w=0.39u l=0.6u
XM7 VSS RN n6 VSUBS nfet_05v0 w=0.39u l=0.6u
XM8 n7 n4 VSS VSUBS nfet_05v0 w=0.39u l=0.6u
XM9 n8 n1 n7 VSUBS nfet_05v0 w=0.39u l=0.6u
XM10 n9 n2 n8 VSUBS nfet_05v0 w=0.39u l=0.6u
XM11 VSS n10 n9 VSUBS nfet_05v0 w=0.39u l=0.6u
XM12 n11 RN VSS VSUBS nfet_05v0 w=0.39u l=0.6u
XM13 n10 n8 n11 VSUBS nfet_05v0 w=0.4u l=0.6u
XM14 Q n10 VSS VSUBS nfet_05v0 w=0.795u l=0.6u
XM15 VDD CLKN n1 VNW pfet_05v0 w=0.865u l=0.5u
XM16 n2 n1 VDD VNW pfet_05v0 w=0.865u l=0.5u
XM17 n3 D VDD VNW pfet_05v0 w=0.76u l=0.5u
XM18 n4 n1 n3 VNW pfet_05v0 w=0.76u l=0.5u
XM19 n12 n2 n4 VNW pfet_05v0 w=0.76u l=0.5u
XM20 VDD n7 n12 VNW pfet_05v0 w=0.76u l=0.5u
XM21 n12 RN VDD VNW pfet_05v0 w=0.76u l=0.5u
XM22 n7 n4 VDD VNW pfet_05v0 w=0.505u l=0.5u
XM23 n8 n2 n7 VNW pfet_05v0 w=0.505u l=0.5u
XM24 n9 n1 n8 VNW pfet_05v0 w=0.505u l=0.5u
XM25 VDD n10 n9 VNW pfet_05v0 w=0.505u l=0.5u
XM26 n10 RN VDD VNW pfet_05v0 w=0.94u l=0.5u
XM27 VDD n8 n10 VNW pfet_05v0 w=0.94u l=0.5u
XM28 Q n10 VDD VNW pfet_05v0 w=1.175u l=0.5u
.ends

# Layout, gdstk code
import gdstk
lib = gdstk.Library(unit=1e-6, precision=1e-09)
def R(c, l, rs):  # rectangles x0, y0, x1, y1
    for r in rs: c.add(gdstk.rectangle(r[:2], r[2:], *l))
def A(c, l, x, y, w, h, nx, ny, dx, dy):  # array of equal rectangles
    R(c, l, [(x+i*dx, y+j*dy, x+i*dx+w, y+j*dy+h) for i in range(nx) for j in range(ny)])
def P(c, l, *ps):  # polygons
    for p in ps: c.add(gdstk.Polygon(p, *l))
boundary = (0, 0)
nwell = (21, 0)
comp = (22, 0)
poly2 = (30, 0)
pplus = (31, 0)
nplus = (32, 0)
contact = (33, 0)
metal1 = (34, 0)
dualgate = (55, 0)
v5_xtor = (112, 1)
lvpwell = (204, 0)

gf180mcu_fd_sc_mcu7t5v0_ = lib.new_cell('gf180mcu_fd_sc_mcu7t5v0__dffnrnq_1')
R(gf180mcu_fd_sc_mcu7t5v0_, boundary, [(0,0,19.04,3.92)])
P(gf180mcu_fd_sc_mcu7t5v0_, nwell, [(-0.43,1.76),(-0.43,4.35),(19.47,4.35),(19.47,1.76),(17.04,1.76),(17.04,1.885),(9.525,1.885),(9.525,1.77),(2.96,1.77),(2.96,1.76)])
R(gf180mcu_fd_sc_mcu7t5v0_, comp, [(17.25,0.345,18.73,1.14), (0.18,0.62,2.78,1.025), (0.28,2.36,2.68,3.225), (17.35,2.405,18.73,3.58)])
P(gf180mcu_fd_sc_mcu7t5v0_, comp, [(3.16,2.38),(3.16,3.14),(7.58,3.14),(7.58,3.3),(7.94,3.3),(7.94,3.14),(9.18,3.14),(9.18,2.38)],
  [(8.52,0.62),(8.52,0.78),(3.14,0.78),(3.14,1.17),(10.08,1.17),(10.08,1.285),(10.44,1.285),(10.44,1.17),(11.64,1.17),(11.64,1.285),(12,1.285),(12,1.17),(16.89,1.17),(16.89,0.77),(15.45,0.77),(15.45,0.78),(8.88,0.78),(8.88,0.62)],
  [(9.54,2.635),(9.54,3.14),(14.21,3.14),(14.21,3.575),(16.89,3.575),(16.89,2.635)])
R(gf180mcu_fd_sc_mcu7t5v0_, poly2, [(10.74,0.56,11.34,1.63), (12.315,2.175,12.815,3.36)])
P(gf180mcu_fd_sc_mcu7t5v0_, poly2, [(0.62,0.4),(0.62,1.245),(0.72,1.245),(0.72,3.45),(1.22,3.45),(1.22,0.4)],
  [(3.58,0.56),(3.58,1.39),(3.6,1.39),(3.6,3.36),(4.1,3.36),(4.1,1.39),(4.18,1.39),(4.18,0.56)],
  [(1.74,0.12),(1.74,3.8),(5.12,3.8),(5.12,2.16),(4.62,2.16),(4.62,3.6),(2.24,3.6),(2.24,1.245),(2.34,1.245),(2.34,0.32),(5.92,0.32),(5.92,1.39),(6.16,1.39),(6.16,1.63),(6.52,1.63),(6.52,0.12)],
  [(6.78,0.56),(6.78,3.36),(7.28,3.36),(7.28,1.39),(7.38,1.39),(7.38,0.56)],
  [(9.18,0.56),(9.18,2.08),(9.98,2.08),(9.98,3.36),(10.48,3.36),(10.48,1.88),(9.78,1.88),(9.78,0.56)],
  [(4.7,0.56),(4.7,1.905),(5.64,1.905),(5.64,3.8),(11.69,3.8),(11.69,2.07),(12.075,2.07),(12.075,1.785),(12.91,1.785),(12.91,0.56),(12.31,0.56),(12.31,1.585),(11.875,1.585),(11.875,1.87),(11.19,1.87),(11.19,3.6),(6.14,3.6),(6.14,2.16),(5.84,2.16),(5.84,1.705),(5.3,1.705),(5.3,0.56)],
  [(13.43,0.56),(13.43,1.505),(13.41,1.505),(13.41,3.36),(13.91,3.36),(13.91,1.455),(14.03,1.455),(14.03,0.56)],
  [(7.62,0.12),(7.62,2.08),(8.24,2.08),(8.24,3.36),(8.74,3.36),(8.74,1.715),(8.22,1.715),(8.22,0.32),(14.55,0.32),(14.55,1.39),(14.65,1.39),(14.65,3.8),(15.15,3.8),(15.15,0.12)],
  [(15.85,0.12),(15.85,1.44),(15.95,1.44),(15.95,3.8),(16.45,3.8),(16.45,0.12)],
  [(17.69,0.12),(17.69,1.8),(17.79,1.8),(17.79,3.8),(18.29,3.8),(18.29,0.12)])
P(gf180mcu_fd_sc_mcu7t5v0_, pplus, [(-0.2,1.76),(-0.2,4.12),(19.24,4.12),(19.24,1.76),(17.04,1.76),(17.04,1.885),(9.525,1.885),(9.525,1.77),(2.96,1.77),(2.96,1.76)])
P(gf180mcu_fd_sc_mcu7t5v0_, nplus, [(-0.2,-0.2),(-0.2,1.76),(2.96,1.76),(2.96,1.77),(9.525,1.77),(9.525,1.885),(17.04,1.885),(17.04,1.76),(19.24,1.76),(19.24,-0.2)])
A(gf180mcu_fd_sc_mcu7t5v0_, contact, 0.25, 0.69, 0.22, 0.22, 3, 1, 1.12, 0)
A(gf180mcu_fd_sc_mcu7t5v0_, contact, 3.21, 0.85, 0.22, 0.22, 3, 1, 1.12, 0)
R(gf180mcu_fd_sc_mcu7t5v0_, contact, [(17.32,0.605,17.54,0.825), (18.44,0.605,18.66,0.825), (8.59,0.69,8.81,0.91), (14.18,0.85,14.4,1.07), (16.6,0.85,16.82,1.07), (13.06,0.88,13.28,1.1), (10.15,0.995,10.37,1.215), (11.71,0.995,11.93,1.215), (1.81,1.27,2.03,1.49), (6.23,1.34,6.45,1.56), (11.03,1.34,11.25,1.56), (14.86,1.355,15.08,1.575), (17.76,1.51,17.98,1.73), (4.79,1.615,5.01,1.835), (6.99,1.63,7.21,1.85), (0.79,1.82,1.01,2.04), (3.67,1.835,3.89,2.055), (16.16,2.095,16.38,2.315), (10.05,2.245,10.27,2.465), (12.4,2.245,12.62,2.465), (13.62,2.245,13.84,2.465), (4.25,2.52,4.47,2.74), (5.27,2.52,5.49,2.74), (0.35,2.525,0.57,2.745), (2.39,2.525,2.61,2.745), (18.44,2.54,18.66,2.76), (13.04,2.705,13.26,2.925), (15.51,2.705,15.73,2.925), (16.6,2.75,16.82,2.97), (6.29,2.835,6.51,3.055), (8.89,2.835,9.11,3.055), (3.23,2.85,3.45,3.07), (9.61,2.85,9.83,3.07), (10.63,2.85,10.85,3.07), (11.88,2.85,12.1,3.07), (1.37,2.935,1.59,3.155), (7.65,3.01,7.87,3.23), (18.44,3.01,18.66,3.23), (16.6,3.22,16.82,3.44), (17.42,3.22,17.64,3.44), (14.28,3.285,14.5,3.505)])
R(gf180mcu_fd_sc_mcu7t5v0_, metal1, [(4.245,0.79,4.555,2.8), (12.98,0.82,13.32,2.93), (0.29,1.77,1.575,2.15), (2.89,1.77,3.895,2.15)])
P(gf180mcu_fd_sc_mcu7t5v0_, metal1, [(0.245,0.63),(0.245,1.375),(1.805,1.375),(1.805,2.465),(0.345,2.465),(0.345,2.805),(0.575,2.805),(0.575,2.7),(2.035,2.7),(2.035,1.145),(0.475,1.145),(0.475,0.63)],
  [(2.385,0.63),(2.385,2.805),(2.615,2.805),(2.615,2.61),(3.785,2.61),(3.785,3.39),(5.015,3.39),(5.015,1.555),(4.785,1.555),(4.785,3.16),(4.015,3.16),(4.015,2.38),(2.615,2.38),(2.615,0.97),(2.715,0.97),(2.715,0.63)],
  [(6.285,2.545),(6.285,3.115),(6.515,3.115),(6.515,2.775),(8.16,2.775),(8.16,3.06),(9.17,3.06),(9.17,2.83),(8.39,2.83),(8.39,2.545)],
  [(5.265,0.79),(5.265,2.8),(5.495,2.8),(5.495,2.315),(8.62,2.315),(8.62,2.47),(10.33,2.47),(10.33,2.24),(8.85,2.24),(8.85,2.085),(5.675,2.085),(5.675,0.79)],
  [(10.09,0.99),(10.09,1.625),(6.93,1.625),(6.93,1.855),(10.06,1.855),(10.06,2.01),(10.625,2.01),(10.625,3.13),(10.855,3.13),(10.855,1.78),(10.43,1.78),(10.43,0.99)],
  [(9.1,0.53),(9.1,1.165),(6.17,1.165),(6.17,1.565),(6.515,1.565),(6.515,1.395),(9.33,1.395),(9.33,0.76),(11.025,0.76),(11.025,1.62),(11.255,1.62),(11.255,0.76),(12.395,0.76),(12.395,2.525),(12.625,2.525),(12.625,0.53)],
  [(14.65,0.6),(14.65,1.83),(15.14,1.83),(15.14,1.02),(16.3,1.02),(16.3,0.6)],
  [(11.645,0.99),(11.645,2.405),(11.875,2.405),(11.875,3.39),(13.9,3.39),(13.9,3.05),(14.79,3.05),(14.79,3.39),(16.365,3.39),(16.365,2.375),(16.385,2.375),(16.385,2.035),(16.135,2.035),(16.135,3.16),(15.02,3.16),(15.02,2.815),(13.67,2.815),(13.67,3.16),(12.105,3.16),(12.105,2.065),(11.995,2.065),(11.995,0.99)],
  [(16.595,0.79),(16.595,1.505),(15.56,1.505),(15.56,2.235),(13.56,2.235),(13.56,2.47),(15.45,2.47),(15.45,2.93),(15.79,2.93),(15.79,1.735),(18.04,1.735),(18.04,1.505),(16.825,1.505),(16.825,0.79)],
  [(18.38,0.6),(18.38,0.83),(18.57,0.83),(18.57,2.33),(17.45,2.33),(17.45,2.765),(18.365,2.765),(18.365,3.32),(18.92,3.32),(18.92,0.6)],
  [(0,-0.3),(0,0.3),(1.31,0.3),(1.31,0.915),(1.65,0.915),(1.65,0.3),(3.15,0.3),(3.15,1.075),(3.49,1.075),(3.49,0.3),(8.53,0.3),(8.53,0.915),(8.87,0.915),(8.87,0.3),(14.175,0.3),(14.175,1.13),(14.405,1.13),(14.405,0.3),(17.315,0.3),(17.315,0.93),(17.545,0.93),(17.545,0.3),(19.04,0.3),(19.04,-0.3)],
  [(16.595,2.69),(16.595,3.62),(14.56,3.62),(14.56,3.28),(14.22,3.28),(14.22,3.62),(9.835,3.62),(9.835,2.79),(9.605,2.79),(9.605,3.62),(7.93,3.62),(7.93,3.005),(7.59,3.005),(7.59,3.62),(3.51,3.62),(3.51,2.845),(3.17,2.845),(3.17,3.62),(1.65,3.62),(1.65,2.93),(1.31,2.93),(1.31,3.62),(0,3.62),(0,4.22),(19.04,4.22),(19.04,3.62),(17.645,3.62),(17.645,3.16),(17.415,3.16),(17.415,3.62),(16.825,3.62),(16.825,2.69)])
R(gf180mcu_fd_sc_mcu7t5v0_, dualgate, [(-0.28,-0.28,19.32,4.2)])
R(gf180mcu_fd_sc_mcu7t5v0_, v5_xtor, [(0,0,19.04,3.92)])
P(gf180mcu_fd_sc_mcu7t5v0_, lvpwell, [(-0.43,-0.43),(-0.43,1.76),(2.96,1.76),(2.96,1.77),(9.525,1.77),(9.525,1.885),(17.04,1.885),(17.04,1.76),(19.47,1.76),(19.47,-0.43)])
gf180mcu_fd_sc_mcu7t5v0_.add(gdstk.Label('D', (3.64,1.96), layer=34, texttype=10))
gf180mcu_fd_sc_mcu7t5v0_.add(gdstk.Label('VSS', (1.4,0), layer=34, texttype=10))
gf180mcu_fd_sc_mcu7t5v0_.add(gdstk.Label('CLKN', (0.84,1.96), layer=34, texttype=10))
gf180mcu_fd_sc_mcu7t5v0_.add(gdstk.Label('RN', (15.4,0.84), layer=34, texttype=10))
gf180mcu_fd_sc_mcu7t5v0_.add(gdstk.Label('Q', (18.76,1.96), layer=34, texttype=10))
gf180mcu_fd_sc_mcu7t5v0_.add(gdstk.Label('VDD', (1.4,3.92), layer=34, texttype=10))
gf180mcu_fd_sc_mcu7t5v0_.add(gdstk.Label('& Vendor GLOBALFOUNDRIES', (0,2), layer=63, texttype=63))
gf180mcu_fd_sc_mcu7t5v0_.add(gdstk.Label('& Product GF018hv5v_mcu_sc7', (0,1.5), layer=63, texttype=63))
gf180mcu_fd_sc_mcu7t5v0_.add(gdstk.Label('& Version 2015q2v1', (0,1), layer=63, texttype=63))
gf180mcu_fd_sc_mcu7t5v0_.add(gdstk.Label('& Metric 1.00', (0,0.5), layer=63, texttype=63))
gf180mcu_fd_sc_mcu7t5v0_.add(gdstk.Label('VNW', (0.345,3.92), layer=21, texttype=10))
gf180mcu_fd_sc_mcu7t5v0_.add(gdstk.Label('VPW', (0.34,-0.085), layer=204, texttype=10))

lib.write_gds('gf180mcu_fd_sc_mcu7t5v0__dffnrnq_1.gds')
